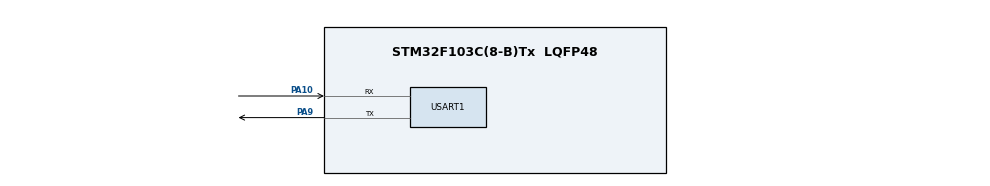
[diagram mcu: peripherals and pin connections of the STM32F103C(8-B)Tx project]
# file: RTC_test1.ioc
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Mcu.Family=STM32F1
Mcu.Name=STM32F103C(8-B)Tx
Mcu.Package=LQFP48
NVIC.PriorityGroup=NVIC_PRIORITYGROUP_4
NVIC.RTC_IRQn=true\:0\:0\:false\:false\:true\:true\:true
PA10.Mode=Asynchronous
PA10.Signal=USART1_RX
PA13.Signal=SYS_JTMS-SWDIO
PA14.Signal=SYS_JTCK-SWCLK
PA9.Mode=Asynchronous
PA9.Signal=USART1_TX
PC14-OSC32_IN.Mode=LSE-External-Oscillator
PC14-OSC32_IN.Signal=RCC_OSC32_IN
PC15-OSC32_OUT.Mode=LSE-External-Oscillator
PC15-OSC32_OUT.Signal=RCC_OSC32_OUT
PD0-OSC_IN.Mode=HSE-External-Oscillator
PD0-OSC_IN.Signal=RCC_OSC_IN
PD1-OSC_OUT.Mode=HSE-External-Oscillator
PD1-OSC_OUT.Signal=RCC_OSC_OUT
ProjectManager.HeapSize=0x200
ProjectManager.StackSize=0x400
ProjectManager.TargetToolchain=MDK-ARM V5.32
RCC.APB1Freq_Value=8000000
RCC.APB2Freq_Value=8000000
RTC.Hours=19
RTC.Minutes=18
RTC.Seconds=34
USART1.VirtualMode=VM_ASYNC
VP_RTC_No_RTC_Output.Mode=RTC_OUT_NO
VP_RTC_VS_RTC_Activate.Mode=RTC_Enabled
VP_RTC_VS_RTC_Calendar.Mode=RTC_Calendar
VP_SYS_VS_ND.Mode=No_Debug
board=custom

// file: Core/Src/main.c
/* USER CODE BEGIN Header */
/**
  ******************************************************************************
  * @file           : main.c
  * @brief          : Main program body
  ******************************************************************************
  * @attention
  *
  * <h2><center>&copy; Copyright (c) 2021 STMicroelectronics.
  * All rights reserved.</center></h2>
  *
  * This software component is licensed by ST under BSD 3-Clause license,
  * the "License"; You may not use this file except in compliance with the
  * License. You may obtain a copy of the License at:
  *                        opensource.org/licenses/BSD-3-Clause
  *
  ******************************************************************************
  */
/* USER CODE END Header */
#include "main.h"
#include "rtc.h"
#include "usart.h"
#include "gpio.h"

/* USER CODE BEGIN PTD */
RTC_DateTypeDef GetData;  //��ȡ���ڽṹ��

RTC_TimeTypeDef GetTime;   //��ȡʱ��ṹ��

/* USER CODE END PTD */

void SystemClock_Config(void);

int main(void)
{

  /* MCU Configuration--------------------------------------------------------*/

  /* Reset of all peripherals, Initializes the Flash interface and the Systick. */
  HAL_Init();

  /* Configure the system clock */
  SystemClock_Config();

  /* Initialize all configured peripherals */
  MX_GPIO_Init();
  MX_RTC_Init();
  MX_USART1_UART_Init();

  /* Infinite loop */
  /* USER CODE BEGIN WHILE */
  while (1)
  {
 	  /* Get the RTC current Time */
	  HAL_RTC_GetTime(&hrtc, &GetTime, RTC_FORMAT_BIN);
      /* Get the RTC current Date */
  	  HAL_RTC_GetDate(&hrtc, &GetData, RTC_FORMAT_BIN);

      /* Display date Format : yy/mm/dd */
      printf("%02d/%02d/%02d\r\n",2000 + GetData.Year, GetData.Month, GetData.Date);
      /* Display time Format : hh:mm:ss */
  	  printf("%02d:%02d:%02d\r\n",GetTime.Hours, GetTime.Minutes, GetTime.Seconds);

  	  printf("\r\n");

  	  HAL_Delay(1000);

  }
  /* USER CODE END 3 */
}

void SystemClock_Config(void)
{
  RCC_OscInitTypeDef RCC_OscInitStruct = {0};
  RCC_ClkInitTypeDef RCC_ClkInitStruct = {0};
  RCC_PeriphCLKInitTypeDef PeriphClkInit = {0};

  /** Initializes the RCC Oscillators according to the specified parameters
  * in the RCC_OscInitTypeDef structure.
  */
  RCC_OscInitStruct.OscillatorType = RCC_OSCILLATORTYPE_HSE|RCC_OSCILLATORTYPE_LSE;
  RCC_OscInitStruct.HSEState = RCC_HSE_ON;
  RCC_OscInitStruct.HSEPredivValue = RCC_HSE_PREDIV_DIV1;
  RCC_OscInitStruct.LSEState = RCC_LSE_ON;
  RCC_OscInitStruct.HSIState = RCC_HSI_ON;
  RCC_OscInitStruct.PLL.PLLState = RCC_PLL_ON;
  RCC_OscInitStruct.PLL.PLLSource = RCC_PLLSOURCE_HSE;
  RCC_OscInitStruct.PLL.PLLMUL = RCC_PLL_MUL9;
  if (HAL_RCC_OscConfig(&RCC_OscInitStruct) != HAL_OK)
  {
    Error_Handler();
  }
  /** Initializes the CPU, AHB and APB buses clocks
  */
  RCC_ClkInitStruct.ClockType = RCC_CLOCKTYPE_HCLK|RCC_CLOCKTYPE_SYSCLK
                              |RCC_CLOCKTYPE_PCLK1|RCC_CLOCKTYPE_PCLK2;
  RCC_ClkInitStruct.SYSCLKSource = RCC_SYSCLKSOURCE_PLLCLK;
  RCC_ClkInitStruct.AHBCLKDivider = RCC_SYSCLK_DIV1;
  RCC_ClkInitStruct.APB1CLKDivider = RCC_HCLK_DIV2;
  RCC_ClkInitStruct.APB2CLKDivider = RCC_HCLK_DIV1;

  if (HAL_RCC_ClockConfig(&RCC_ClkInitStruct, FLASH_LATENCY_2) != HAL_OK)
  {
    Error_Handler();
  }
  PeriphClkInit.PeriphClockSelection = RCC_PERIPHCLK_RTC;
  PeriphClkInit.RTCClockSelection = RCC_RTCCLKSOURCE_LSE;
  if (HAL_RCCEx_PeriphCLKConfig(&PeriphClkInit) != HAL_OK)
  {
    Error_Handler();
  }
}

void Error_Handler(void)
{
  __disable_irq();
  while (1)
  {
  }
}

/************************ (C) COPYRIGHT STMicroelectronics *****END OF FILE****/
